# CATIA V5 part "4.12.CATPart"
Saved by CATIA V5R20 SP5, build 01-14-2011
Part number: 螺母特征参数化建模
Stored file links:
  E:\scc\4.12.CATPart

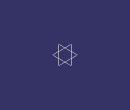
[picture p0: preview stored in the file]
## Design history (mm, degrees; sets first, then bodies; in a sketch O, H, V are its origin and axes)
Body1 (main body)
